VERSION 5.7 ;
  NOWIREEXTENSIONATPIN ON ;
  DIVIDERCHAR "/" ;
  BUSBITCHARS "[]" ;
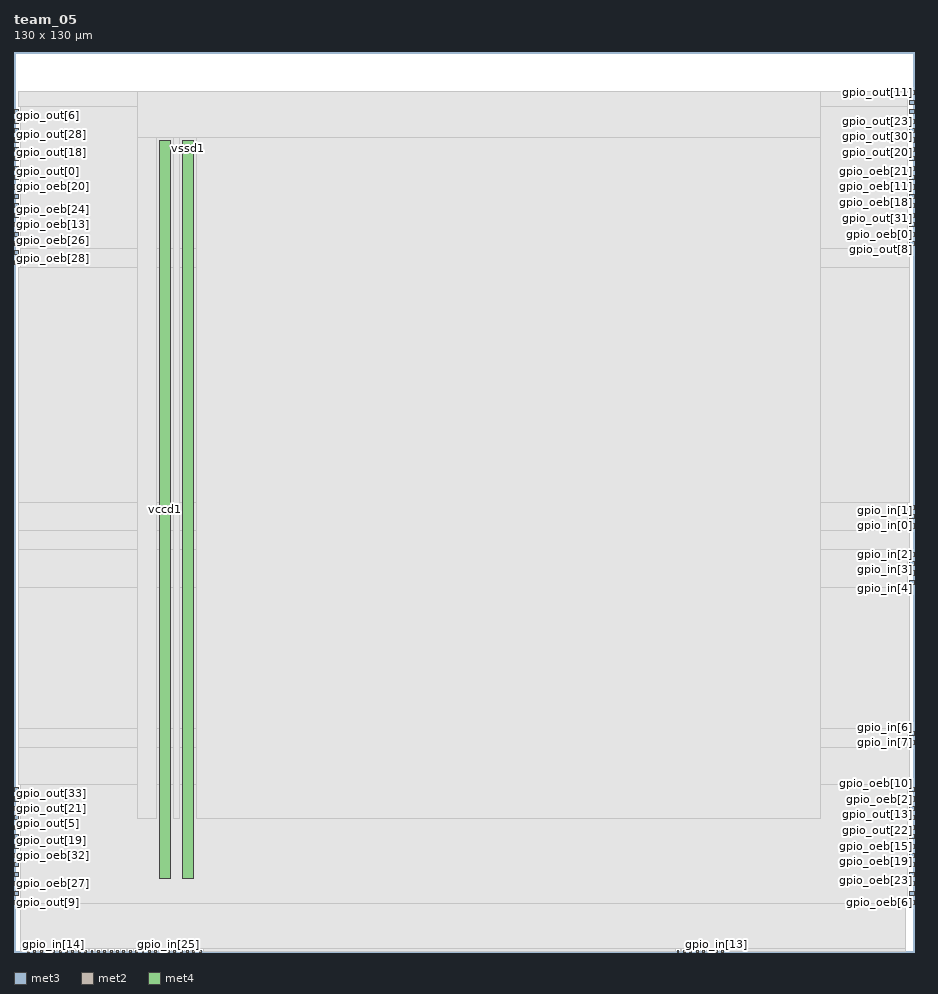
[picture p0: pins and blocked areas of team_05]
MACRO team_05
  CLASS BLOCK ;
  FOREIGN team_05 ;
  ORIGIN 0.000 0.000 ;
  SIZE 130.000 BY 130.000 ;
  PIN clk
    DIRECTION INPUT ;
    USE SIGNAL ;
    ANTENNAGATEAREA 1.286700 ;
    ANTENNADIFFAREA 0.434700 ;
    PORT
      LAYER met3 ;
        RECT 0.000 99.320 0.600 99.920 ;
    END
  END clk
  PIN en
    DIRECTION INPUT ;
    USE SIGNAL ;
    ANTENNAGATEAREA 0.647700 ;
    ANTENNADIFFAREA 0.434700 ;
    PORT
      LAYER met2 ;
        RECT 96.690 0.000 96.970 0.280 ;
    END
  END en
  PIN gpio_in[0]
    DIRECTION INPUT ;
    USE SIGNAL ;
    ANTENNAGATEAREA 0.647700 ;
    ANTENNADIFFAREA 0.434700 ;
    PORT
      LAYER met3 ;
        RECT 129.400 61.240 130.000 61.840 ;
    END
  END gpio_in[0]
  PIN gpio_in[10]
    DIRECTION INPUT ;
    USE SIGNAL ;
    ANTENNAGATEAREA 0.647700 ;
    ANTENNADIFFAREA 0.434700 ;
    PORT
      LAYER met2 ;
        RECT 99.450 0.000 99.730 0.280 ;
    END
  END gpio_in[10]
  PIN gpio_in[11]
    DIRECTION INPUT ;
    USE SIGNAL ;
    ANTENNAGATEAREA 0.647700 ;
    ANTENNADIFFAREA 0.434700 ;
    PORT
      LAYER met2 ;
        RECT 102.210 0.000 102.490 0.280 ;
    END
  END gpio_in[11]
  PIN gpio_in[12]
    DIRECTION INPUT ;
    USE SIGNAL ;
    ANTENNAGATEAREA 0.647700 ;
    ANTENNADIFFAREA 0.434700 ;
    PORT
      LAYER met2 ;
        RECT 100.370 0.000 100.650 0.280 ;
    END
  END gpio_in[12]
  PIN gpio_in[13]
    DIRECTION INPUT ;
    USE SIGNAL ;
    ANTENNAGATEAREA 0.647700 ;
    ANTENNADIFFAREA 0.434700 ;
    PORT
      LAYER met2 ;
        RECT 101.290 0.000 101.570 0.280 ;
    END
  END gpio_in[13]
  PIN gpio_in[14]
    DIRECTION INPUT ;
    USE SIGNAL ;
    PORT
      LAYER met2 ;
        RECT 5.610 0.000 5.890 0.280 ;
    END
  END gpio_in[14]
  PIN gpio_in[15]
    DIRECTION INPUT ;
    USE SIGNAL ;
    PORT
      LAYER met2 ;
        RECT 8.370 0.000 8.650 0.280 ;
    END
  END gpio_in[15]
  PIN gpio_in[16]
    DIRECTION INPUT ;
    USE SIGNAL ;
    PORT
      LAYER met2 ;
        RECT 23.090 0.000 23.370 0.280 ;
    END
  END gpio_in[16]
  PIN gpio_in[17]
    DIRECTION INPUT ;
    USE SIGNAL ;
    PORT
      LAYER met2 ;
        RECT 7.450 0.000 7.730 0.280 ;
    END
  END gpio_in[17]
  PIN gpio_in[18]
    DIRECTION INPUT ;
    USE SIGNAL ;
    PORT
      LAYER met2 ;
        RECT 6.530 0.000 6.810 0.280 ;
    END
  END gpio_in[18]
  PIN gpio_in[19]
    DIRECTION INPUT ;
    USE SIGNAL ;
    PORT
      LAYER met2 ;
        RECT 9.290 0.000 9.570 0.280 ;
    END
  END gpio_in[19]
  PIN gpio_in[1]
    DIRECTION INPUT ;
    USE SIGNAL ;
    ANTENNAGATEAREA 0.647700 ;
    ANTENNADIFFAREA 0.434700 ;
    PORT
      LAYER met3 ;
        RECT 129.400 62.600 130.000 63.200 ;
    END
  END gpio_in[1]
  PIN gpio_in[20]
    DIRECTION INPUT ;
    USE SIGNAL ;
    PORT
      LAYER met2 ;
        RECT 19.410 0.000 19.690 0.280 ;
    END
  END gpio_in[20]
  PIN gpio_in[21]
    DIRECTION INPUT ;
    USE SIGNAL ;
    PORT
      LAYER met2 ;
        RECT 11.130 0.000 11.410 0.280 ;
    END
  END gpio_in[21]
  PIN gpio_in[22]
    DIRECTION INPUT ;
    USE SIGNAL ;
    PORT
      LAYER met2 ;
        RECT 10.210 0.000 10.490 0.280 ;
    END
  END gpio_in[22]
  PIN gpio_in[23]
    DIRECTION INPUT ;
    USE SIGNAL ;
    PORT
      LAYER met2 ;
        RECT 20.330 0.000 20.610 0.280 ;
    END
  END gpio_in[23]
  PIN gpio_in[24]
    DIRECTION INPUT ;
    USE SIGNAL ;
    PORT
      LAYER met2 ;
        RECT 1.930 0.000 2.210 0.280 ;
    END
  END gpio_in[24]
  PIN gpio_in[25]
    DIRECTION INPUT ;
    USE SIGNAL ;
    PORT
      LAYER met2 ;
        RECT 22.170 0.000 22.450 0.280 ;
    END
  END gpio_in[25]
  PIN gpio_in[26]
    DIRECTION INPUT ;
    USE SIGNAL ;
    PORT
      LAYER met2 ;
        RECT 4.690 0.000 4.970 0.280 ;
    END
  END gpio_in[26]
  PIN gpio_in[27]
    DIRECTION INPUT ;
    USE SIGNAL ;
    PORT
      LAYER met2 ;
        RECT 3.770 0.000 4.050 0.280 ;
    END
  END gpio_in[27]
  PIN gpio_in[28]
    DIRECTION INPUT ;
    USE SIGNAL ;
    PORT
      LAYER met2 ;
        RECT 26.770 0.000 27.050 0.280 ;
    END
  END gpio_in[28]
  PIN gpio_in[29]
    DIRECTION INPUT ;
    USE SIGNAL ;
    PORT
      LAYER met2 ;
        RECT 25.850 0.000 26.130 0.280 ;
    END
  END gpio_in[29]
  PIN gpio_in[2]
    DIRECTION INPUT ;
    USE SIGNAL ;
    ANTENNAGATEAREA 0.647700 ;
    ANTENNADIFFAREA 0.434700 ;
    PORT
      LAYER met3 ;
        RECT 129.400 57.160 130.000 57.760 ;
    END
  END gpio_in[2]
  PIN gpio_in[30]
    DIRECTION INPUT ;
    USE SIGNAL ;
    PORT
      LAYER met2 ;
        RECT 24.930 0.000 25.210 0.280 ;
    END
  END gpio_in[30]
  PIN gpio_in[31]
    DIRECTION INPUT ;
    USE SIGNAL ;
    PORT
      LAYER met2 ;
        RECT 24.010 0.000 24.290 0.280 ;
    END
  END gpio_in[31]
  PIN gpio_in[32]
    DIRECTION INPUT ;
    USE SIGNAL ;
    PORT
      LAYER met2 ;
        RECT 2.850 0.000 3.130 0.280 ;
    END
  END gpio_in[32]
  PIN gpio_in[33]
    DIRECTION INPUT ;
    USE SIGNAL ;
    PORT
      LAYER met2 ;
        RECT 21.250 0.000 21.530 0.280 ;
    END
  END gpio_in[33]
  PIN gpio_in[3]
    DIRECTION INPUT ;
    USE SIGNAL ;
    ANTENNAGATEAREA 0.647700 ;
    ANTENNADIFFAREA 0.434700 ;
    PORT
      LAYER met3 ;
        RECT 129.400 55.800 130.000 56.400 ;
    END
  END gpio_in[3]
  PIN gpio_in[4]
    DIRECTION INPUT ;
    USE SIGNAL ;
    ANTENNAGATEAREA 0.647700 ;
    ANTENNADIFFAREA 0.434700 ;
    PORT
      LAYER met3 ;
        RECT 129.400 53.080 130.000 53.680 ;
    END
  END gpio_in[4]
  PIN gpio_in[5]
    DIRECTION INPUT ;
    USE SIGNAL ;
    ANTENNAGATEAREA 0.647700 ;
    ANTENNADIFFAREA 0.434700 ;
    PORT
      LAYER met3 ;
        RECT 129.400 54.440 130.000 55.040 ;
    END
  END gpio_in[5]
  PIN gpio_in[6]
    DIRECTION INPUT ;
    USE SIGNAL ;
    ANTENNAGATEAREA 0.647700 ;
    ANTENNADIFFAREA 0.434700 ;
    PORT
      LAYER met3 ;
        RECT 129.400 31.320 130.000 31.920 ;
    END
  END gpio_in[6]
  PIN gpio_in[7]
    DIRECTION INPUT ;
    USE SIGNAL ;
    ANTENNAGATEAREA 0.647700 ;
    ANTENNADIFFAREA 0.434700 ;
    PORT
      LAYER met3 ;
        RECT 129.400 29.960 130.000 30.560 ;
    END
  END gpio_in[7]
  PIN gpio_in[8]
    DIRECTION INPUT ;
    USE SIGNAL ;
    ANTENNAGATEAREA 0.647700 ;
    ANTENNADIFFAREA 0.434700 ;
    PORT
      LAYER met2 ;
        RECT 97.610 0.000 97.890 0.280 ;
    END
  END gpio_in[8]
  PIN gpio_in[9]
    DIRECTION INPUT ;
    USE SIGNAL ;
    ANTENNAGATEAREA 0.647700 ;
    ANTENNADIFFAREA 0.434700 ;
    PORT
      LAYER met2 ;
        RECT 98.530 0.000 98.810 0.280 ;
    END
  END gpio_in[9]
  PIN gpio_oeb[0]
    DIRECTION OUTPUT ;
    USE SIGNAL ;
    PORT
      LAYER met3 ;
        RECT 129.400 103.400 130.000 104.000 ;
    END
  END gpio_oeb[0]
  PIN gpio_oeb[10]
    DIRECTION OUTPUT ;
    USE SIGNAL ;
    PORT
      LAYER met3 ;
        RECT 129.400 23.160 130.000 23.760 ;
    END
  END gpio_oeb[10]
  PIN gpio_oeb[11]
    DIRECTION OUTPUT ;
    USE SIGNAL ;
    PORT
      LAYER met3 ;
        RECT 129.400 110.200 130.000 110.800 ;
    END
  END gpio_oeb[11]
  PIN gpio_oeb[12]
    DIRECTION OUTPUT ;
    USE SIGNAL ;
    PORT
      LAYER met2 ;
        RECT 18.490 0.000 18.770 0.280 ;
    END
  END gpio_oeb[12]
  PIN gpio_oeb[13]
    DIRECTION OUTPUT ;
    USE SIGNAL ;
    PORT
      LAYER met3 ;
        RECT 0.000 104.760 0.600 105.360 ;
    END
  END gpio_oeb[13]
  PIN gpio_oeb[14]
    DIRECTION OUTPUT ;
    USE SIGNAL ;
    PORT
      LAYER met3 ;
        RECT 0.000 121.080 0.600 121.680 ;
    END
  END gpio_oeb[14]
  PIN gpio_oeb[15]
    DIRECTION OUTPUT ;
    USE SIGNAL ;
    PORT
      LAYER met3 ;
        RECT 129.400 15.000 130.000 15.600 ;
    END
  END gpio_oeb[15]
  PIN gpio_oeb[16]
    DIRECTION OUTPUT ;
    USE SIGNAL ;
    PORT
      LAYER met2 ;
        RECT 12.050 0.000 12.330 0.280 ;
    END
  END gpio_oeb[16]
  PIN gpio_oeb[17]
    DIRECTION OUTPUT ;
    USE SIGNAL ;
    PORT
      LAYER met3 ;
        RECT 0.000 8.200 0.600 8.800 ;
    END
  END gpio_oeb[17]
  PIN gpio_oeb[18]
    DIRECTION OUTPUT ;
    USE SIGNAL ;
    PORT
      LAYER met3 ;
        RECT 129.400 108.840 130.000 109.440 ;
    END
  END gpio_oeb[18]
  PIN gpio_oeb[19]
    DIRECTION OUTPUT ;
    USE SIGNAL ;
    PORT
      LAYER met3 ;
        RECT 129.400 13.640 130.000 14.240 ;
    END
  END gpio_oeb[19]
  PIN gpio_oeb[1]
    DIRECTION OUTPUT ;
    USE SIGNAL ;
    PORT
      LAYER met3 ;
        RECT 129.400 12.280 130.000 12.880 ;
    END
  END gpio_oeb[1]
  PIN gpio_oeb[20]
    DIRECTION OUTPUT ;
    USE SIGNAL ;
    PORT
      LAYER met3 ;
        RECT 0.000 110.200 0.600 110.800 ;
    END
  END gpio_oeb[20]
  PIN gpio_oeb[21]
    DIRECTION OUTPUT ;
    USE SIGNAL ;
    PORT
      LAYER met3 ;
        RECT 129.400 111.560 130.000 112.160 ;
    END
  END gpio_oeb[21]
  PIN gpio_oeb[22]
    DIRECTION OUTPUT ;
    USE SIGNAL ;
    PORT
      LAYER met3 ;
        RECT 0.000 12.280 0.600 12.880 ;
    END
  END gpio_oeb[22]
  PIN gpio_oeb[23]
    DIRECTION OUTPUT ;
    USE SIGNAL ;
    PORT
      LAYER met3 ;
        RECT 129.400 10.920 130.000 11.520 ;
    END
  END gpio_oeb[23]
  PIN gpio_oeb[24]
    DIRECTION OUTPUT ;
    USE SIGNAL ;
    PORT
      LAYER met3 ;
        RECT 0.000 106.120 0.600 106.720 ;
    END
  END gpio_oeb[24]
  PIN gpio_oeb[25]
    DIRECTION OUTPUT ;
    USE SIGNAL ;
    PORT
      LAYER met2 ;
        RECT 15.730 0.000 16.010 0.280 ;
    END
  END gpio_oeb[25]
  PIN gpio_oeb[26]
    DIRECTION OUTPUT ;
    USE SIGNAL ;
    PORT
      LAYER met3 ;
        RECT 0.000 103.400 0.600 104.000 ;
    END
  END gpio_oeb[26]
  PIN gpio_oeb[27]
    DIRECTION OUTPUT ;
    USE SIGNAL ;
    PORT
      LAYER met3 ;
        RECT 0.000 9.560 0.600 10.160 ;
    END
  END gpio_oeb[27]
  PIN gpio_oeb[28]
    DIRECTION OUTPUT ;
    USE SIGNAL ;
    PORT
      LAYER met3 ;
        RECT 0.000 100.680 0.600 101.280 ;
    END
  END gpio_oeb[28]
  PIN gpio_oeb[29]
    DIRECTION OUTPUT ;
    USE SIGNAL ;
    PORT
      LAYER met2 ;
        RECT 14.810 0.000 15.090 0.280 ;
    END
  END gpio_oeb[29]
  PIN gpio_oeb[2]
    DIRECTION OUTPUT ;
    USE SIGNAL ;
    PORT
      LAYER met3 ;
        RECT 129.400 21.800 130.000 22.400 ;
    END
  END gpio_oeb[2]
  PIN gpio_oeb[30]
    DIRECTION OUTPUT ;
    USE SIGNAL ;
    PORT
      LAYER met2 ;
        RECT 13.890 0.000 14.170 0.280 ;
    END
  END gpio_oeb[30]
  PIN gpio_oeb[31]
    DIRECTION OUTPUT ;
    USE SIGNAL ;
    PORT
      LAYER met3 ;
        RECT 0.000 107.480 0.600 108.080 ;
    END
  END gpio_oeb[31]
  PIN gpio_oeb[32]
    DIRECTION OUTPUT ;
    USE SIGNAL ;
    PORT
      LAYER met3 ;
        RECT 0.000 13.640 0.600 14.240 ;
    END
  END gpio_oeb[32]
  PIN gpio_oeb[33]
    DIRECTION OUTPUT ;
    USE SIGNAL ;
    PORT
      LAYER met3 ;
        RECT 129.400 107.480 130.000 108.080 ;
    END
  END gpio_oeb[33]
  PIN gpio_oeb[3]
    DIRECTION OUTPUT ;
    USE SIGNAL ;
    PORT
      LAYER met3 ;
        RECT 129.400 8.200 130.000 8.800 ;
    END
  END gpio_oeb[3]
  PIN gpio_oeb[4]
    DIRECTION OUTPUT ;
    USE SIGNAL ;
    PORT
      LAYER met3 ;
        RECT 0.000 10.920 0.600 11.520 ;
    END
  END gpio_oeb[4]
  PIN gpio_oeb[5]
    DIRECTION OUTPUT ;
    USE SIGNAL ;
    PORT
      LAYER met2 ;
        RECT 12.970 0.000 13.250 0.280 ;
    END
  END gpio_oeb[5]
  PIN gpio_oeb[6]
    DIRECTION OUTPUT ;
    USE SIGNAL ;
    PORT
      LAYER met3 ;
        RECT 129.400 6.840 130.000 7.440 ;
    END
  END gpio_oeb[6]
  PIN gpio_oeb[7]
    DIRECTION OUTPUT ;
    USE SIGNAL ;
    PORT
      LAYER met3 ;
        RECT 0.000 102.040 0.600 102.640 ;
    END
  END gpio_oeb[7]
  PIN gpio_oeb[8]
    DIRECTION OUTPUT ;
    USE SIGNAL ;
    PORT
      LAYER met3 ;
        RECT 129.400 9.560 130.000 10.160 ;
    END
  END gpio_oeb[8]
  PIN gpio_oeb[9]
    DIRECTION OUTPUT ;
    USE SIGNAL ;
    PORT
      LAYER met3 ;
        RECT 0.000 108.840 0.600 109.440 ;
    END
  END gpio_oeb[9]
  PIN gpio_out[0]
    DIRECTION OUTPUT ;
    USE SIGNAL ;
    PORT
      LAYER met3 ;
        RECT 0.000 111.560 0.600 112.160 ;
    END
  END gpio_out[0]
  PIN gpio_out[10]
    DIRECTION OUTPUT ;
    USE SIGNAL ;
    PORT
      LAYER met2 ;
        RECT 17.570 0.000 17.850 0.280 ;
    END
  END gpio_out[10]
  PIN gpio_out[11]
    DIRECTION OUTPUT ;
    USE SIGNAL ;
    PORT
      LAYER met3 ;
        RECT 129.400 123.800 130.000 124.400 ;
    END
  END gpio_out[11]
  PIN gpio_out[12]
    DIRECTION OUTPUT ;
    USE SIGNAL ;
    PORT
      LAYER met3 ;
        RECT 0.000 112.920 0.600 113.520 ;
    END
  END gpio_out[12]
  PIN gpio_out[13]
    DIRECTION OUTPUT ;
    USE SIGNAL ;
    PORT
      LAYER met3 ;
        RECT 129.400 20.440 130.000 21.040 ;
    END
  END gpio_out[13]
  PIN gpio_out[14]
    DIRECTION OUTPUT ;
    USE SIGNAL ;
    ANTENNADIFFAREA 0.702900 ;
    PORT
      LAYER met3 ;
        RECT 129.400 63.960 130.000 64.560 ;
    END
  END gpio_out[14]
  PIN gpio_out[15]
    DIRECTION OUTPUT ;
    USE SIGNAL ;
    PORT
      LAYER met3 ;
        RECT 0.000 23.160 0.600 23.760 ;
    END
  END gpio_out[15]
  PIN gpio_out[16]
    DIRECTION OUTPUT ;
    USE SIGNAL ;
    PORT
      LAYER met3 ;
        RECT 0.000 16.360 0.600 16.960 ;
    END
  END gpio_out[16]
  PIN gpio_out[17]
    DIRECTION OUTPUT ;
    USE SIGNAL ;
    PORT
      LAYER met3 ;
        RECT 0.000 17.720 0.600 18.320 ;
    END
  END gpio_out[17]
  PIN gpio_out[18]
    DIRECTION OUTPUT ;
    USE SIGNAL ;
    PORT
      LAYER met3 ;
        RECT 0.000 114.280 0.600 114.880 ;
    END
  END gpio_out[18]
  PIN gpio_out[19]
    DIRECTION OUTPUT ;
    USE SIGNAL ;
    PORT
      LAYER met3 ;
        RECT 0.000 15.000 0.600 15.600 ;
    END
  END gpio_out[19]
  PIN gpio_out[1]
    DIRECTION OUTPUT ;
    USE SIGNAL ;
    PORT
      LAYER met3 ;
        RECT 129.400 112.920 130.000 113.520 ;
    END
  END gpio_out[1]
  PIN gpio_out[20]
    DIRECTION OUTPUT ;
    USE SIGNAL ;
    PORT
      LAYER met3 ;
        RECT 129.400 114.280 130.000 114.880 ;
    END
  END gpio_out[20]
  PIN gpio_out[21]
    DIRECTION OUTPUT ;
    USE SIGNAL ;
    PORT
      LAYER met3 ;
        RECT 0.000 20.440 0.600 21.040 ;
    END
  END gpio_out[21]
  PIN gpio_out[22]
    DIRECTION OUTPUT ;
    USE SIGNAL ;
    PORT
      LAYER met3 ;
        RECT 129.400 16.360 130.000 16.960 ;
    END
  END gpio_out[22]
  PIN gpio_out[23]
    DIRECTION OUTPUT ;
    USE SIGNAL ;
    PORT
      LAYER met3 ;
        RECT 129.400 119.720 130.000 120.320 ;
    END
  END gpio_out[23]
  PIN gpio_out[24]
    DIRECTION OUTPUT ;
    USE SIGNAL ;
    PORT
      LAYER met3 ;
        RECT 129.400 122.440 130.000 123.040 ;
    END
  END gpio_out[24]
  PIN gpio_out[25]
    DIRECTION OUTPUT ;
    USE SIGNAL ;
    PORT
      LAYER met3 ;
        RECT 0.000 115.640 0.600 116.240 ;
    END
  END gpio_out[25]
  PIN gpio_out[26]
    DIRECTION OUTPUT ;
    USE SIGNAL ;
    PORT
      LAYER met3 ;
        RECT 129.400 121.080 130.000 121.680 ;
    END
  END gpio_out[26]
  PIN gpio_out[27]
    DIRECTION OUTPUT ;
    USE SIGNAL ;
    PORT
      LAYER met3 ;
        RECT 129.400 117.000 130.000 117.600 ;
    END
  END gpio_out[27]
  PIN gpio_out[28]
    DIRECTION OUTPUT ;
    USE SIGNAL ;
    PORT
      LAYER met3 ;
        RECT 0.000 117.000 0.600 117.600 ;
    END
  END gpio_out[28]
  PIN gpio_out[29]
    DIRECTION OUTPUT ;
    USE SIGNAL ;
    PORT
      LAYER met3 ;
        RECT 129.400 106.120 130.000 106.720 ;
    END
  END gpio_out[29]
  PIN gpio_out[2]
    DIRECTION OUTPUT ;
    USE SIGNAL ;
    PORT
      LAYER met2 ;
        RECT 16.650 0.000 16.930 0.280 ;
    END
  END gpio_out[2]
  PIN gpio_out[30]
    DIRECTION OUTPUT ;
    USE SIGNAL ;
    PORT
      LAYER met3 ;
        RECT 129.400 118.360 130.000 118.960 ;
    END
  END gpio_out[30]
  PIN gpio_out[31]
    DIRECTION OUTPUT ;
    USE SIGNAL ;
    PORT
      LAYER met3 ;
        RECT 129.400 104.760 130.000 105.360 ;
    END
  END gpio_out[31]
  PIN gpio_out[32]
    DIRECTION OUTPUT ;
    USE SIGNAL ;
    PORT
      LAYER met3 ;
        RECT 0.000 118.360 0.600 118.960 ;
    END
  END gpio_out[32]
  PIN gpio_out[33]
    DIRECTION OUTPUT ;
    USE SIGNAL ;
    PORT
      LAYER met3 ;
        RECT 0.000 21.800 0.600 22.400 ;
    END
  END gpio_out[33]
  PIN gpio_out[3]
    DIRECTION OUTPUT ;
    USE SIGNAL ;
    PORT
      LAYER met3 ;
        RECT 129.400 19.080 130.000 19.680 ;
    END
  END gpio_out[3]
  PIN gpio_out[4]
    DIRECTION OUTPUT ;
    USE SIGNAL ;
    PORT
      LAYER met3 ;
        RECT 129.400 115.640 130.000 116.240 ;
    END
  END gpio_out[4]
  PIN gpio_out[5]
    DIRECTION OUTPUT ;
    USE SIGNAL ;
    PORT
      LAYER met3 ;
        RECT 0.000 19.080 0.600 19.680 ;
    END
  END gpio_out[5]
  PIN gpio_out[6]
    DIRECTION OUTPUT ;
    USE SIGNAL ;
    PORT
      LAYER met3 ;
        RECT 0.000 119.720 0.600 120.320 ;
    END
  END gpio_out[6]
  PIN gpio_out[7]
    DIRECTION OUTPUT ;
    USE SIGNAL ;
    PORT
      LAYER met3 ;
        RECT 129.400 17.720 130.000 18.320 ;
    END
  END gpio_out[7]
  PIN gpio_out[8]
    DIRECTION OUTPUT ;
    USE SIGNAL ;
    PORT
      LAYER met3 ;
        RECT 129.400 102.040 130.000 102.640 ;
    END
  END gpio_out[8]
  PIN gpio_out[9]
    DIRECTION OUTPUT ;
    USE SIGNAL ;
    PORT
      LAYER met3 ;
        RECT 0.000 6.840 0.600 7.440 ;
    END
  END gpio_out[9]
  PIN nrst
    DIRECTION INPUT ;
    USE SIGNAL ;
    ANTENNAGATEAREA 0.647700 ;
    ANTENNADIFFAREA 0.434700 ;
    PORT
      LAYER met2 ;
        RECT 95.770 0.000 96.050 0.280 ;
    END
  END nrst
  PIN vccd1
    DIRECTION INOUT ;
    USE POWER ;
    PORT
      LAYER met4 ;
        RECT 21.040 10.640 22.640 117.200 ;
    END
  END vccd1
  PIN vssd1
    DIRECTION INOUT ;
    USE GROUND ;
    PORT
      LAYER met4 ;
        RECT 24.340 10.640 25.940 117.200 ;
    END
  END vssd1
  OBS
      LAYER nwell ;
        RECT 5.330 10.760 124.390 117.150 ;
      LAYER li1 ;
        RECT 5.520 10.795 124.200 117.045 ;
      LAYER met1 ;
        RECT 0.990 6.160 128.730 117.200 ;
      LAYER met2 ;
        RECT 1.010 0.560 128.710 122.925 ;
        RECT 1.010 0.070 1.650 0.560 ;
        RECT 2.490 0.070 2.570 0.560 ;
        RECT 3.410 0.070 3.490 0.560 ;
        RECT 4.330 0.070 4.410 0.560 ;
        RECT 5.250 0.070 5.330 0.560 ;
        RECT 6.170 0.070 6.250 0.560 ;
        RECT 7.090 0.070 7.170 0.560 ;
        RECT 8.010 0.070 8.090 0.560 ;
        RECT 8.930 0.070 9.010 0.560 ;
        RECT 9.850 0.070 9.930 0.560 ;
        RECT 10.770 0.070 10.850 0.560 ;
        RECT 11.690 0.070 11.770 0.560 ;
        RECT 12.610 0.070 12.690 0.560 ;
        RECT 13.530 0.070 13.610 0.560 ;
        RECT 14.450 0.070 14.530 0.560 ;
        RECT 15.370 0.070 15.450 0.560 ;
        RECT 16.290 0.070 16.370 0.560 ;
        RECT 17.210 0.070 17.290 0.560 ;
        RECT 18.130 0.070 18.210 0.560 ;
        RECT 19.050 0.070 19.130 0.560 ;
        RECT 19.970 0.070 20.050 0.560 ;
        RECT 20.890 0.070 20.970 0.560 ;
        RECT 21.810 0.070 21.890 0.560 ;
        RECT 22.730 0.070 22.810 0.560 ;
        RECT 23.650 0.070 23.730 0.560 ;
        RECT 24.570 0.070 24.650 0.560 ;
        RECT 25.490 0.070 25.570 0.560 ;
        RECT 26.410 0.070 26.490 0.560 ;
        RECT 27.330 0.070 95.490 0.560 ;
        RECT 96.330 0.070 96.410 0.560 ;
        RECT 97.250 0.070 97.330 0.560 ;
        RECT 98.170 0.070 98.250 0.560 ;
        RECT 99.090 0.070 99.170 0.560 ;
        RECT 100.010 0.070 100.090 0.560 ;
        RECT 100.930 0.070 101.010 0.560 ;
        RECT 101.850 0.070 101.930 0.560 ;
        RECT 102.770 0.070 128.710 0.560 ;
      LAYER met3 ;
        RECT 0.600 122.080 129.000 124.260 ;
        RECT 1.000 101.640 129.000 122.080 ;
        RECT 1.000 98.920 129.400 101.640 ;
        RECT 0.600 64.960 129.400 98.920 ;
        RECT 0.600 60.840 129.000 64.960 ;
        RECT 0.600 58.160 129.400 60.840 ;
        RECT 0.600 52.680 129.000 58.160 ;
        RECT 0.600 32.320 129.400 52.680 ;
        RECT 0.600 29.560 129.000 32.320 ;
        RECT 0.600 24.160 129.400 29.560 ;
        RECT 1.000 6.975 129.000 24.160 ;
      LAYER met4 ;
        RECT 17.775 117.600 116.545 124.265 ;
        RECT 17.775 19.215 20.640 117.600 ;
        RECT 23.040 19.215 23.940 117.600 ;
        RECT 26.340 19.215 116.545 117.600 ;
  END
END team_05
END LIBRARY

